VERSION 5.8 ;
BUSBITCHARS "[]" ;
DIVIDERCHAR "/" ;
UNITS
    DATABASE MICRONS 1000 ;
END UNITS

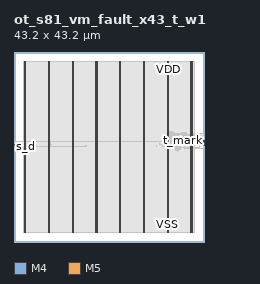
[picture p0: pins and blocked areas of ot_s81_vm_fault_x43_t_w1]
MACRO ot_s81_vm_fault_x43_t_w1
  FOREIGN ot_s81_vm_fault_x43_t_w1 0 0 ;
  CLASS BLOCK ;
  SIZE 43.2 BY 43.2 ;
  PIN b0[0]
    DIRECTION OUTPUT ;
    USE SIGNAL ;
    PORT
      LAYER M4 ;
        RECT  43.116 22.032 43.2 22.056 ;
    END
  END b0[0]
  PIN b0[1]
    DIRECTION OUTPUT ;
    USE SIGNAL ;
    PORT
      LAYER M4 ;
        RECT  43.116 22.128 43.2 22.152 ;
    END
  END b0[1]
  PIN b2[0]
    DIRECTION OUTPUT ;
    USE SIGNAL ;
    PORT
      LAYER M4 ;
        RECT  43.116 22.224 43.2 22.248 ;
    END
  END b2[0]
  PIN b2[1]
    DIRECTION OUTPUT ;
    USE SIGNAL ;
    PORT
      LAYER M4 ;
        RECT  43.116 22.32 43.2 22.344 ;
    END
  END b2[1]
  PIN b3[0]
    DIRECTION OUTPUT ;
    USE SIGNAL ;
    PORT
      LAYER M4 ;
        RECT  43.116 22.416 43.2 22.44 ;
    END
  END b3[0]
  PIN b3[1]
    DIRECTION OUTPUT ;
    USE SIGNAL ;
    PORT
      LAYER M4 ;
        RECT  43.116 22.512 43.2 22.536 ;
    END
  END b3[1]
  PIN bpar[0]
    DIRECTION OUTPUT ;
    USE SIGNAL ;
    PORT
      LAYER M4 ;
        RECT  43.116 22.608 43.2 22.632 ;
    END
  END bpar[0]
  PIN bpar[1]
    DIRECTION OUTPUT ;
    USE SIGNAL ;
    PORT
      LAYER M4 ;
        RECT  43.116 22.704 43.2 22.728 ;
    END
  END bpar[1]
  PIN bpar[2]
    DIRECTION OUTPUT ;
    USE SIGNAL ;
    PORT
      LAYER M4 ;
        RECT  43.116 22.8 43.2 22.824 ;
    END
  END bpar[2]
  PIN ph1_bad
    DIRECTION OUTPUT ;
    USE SIGNAL ;
    PORT
      LAYER M4 ;
        RECT  43.116 22.896 43.2 22.92 ;
    END
  END ph1_bad
  PIN s_d
    DIRECTION INPUT ;
    USE SIGNAL ;
    PORT
      LAYER M4 ;
        RECT  0 21.744 0.084 21.768 ;
    END
  END s_d
  PIN s_v
    DIRECTION INPUT ;
    USE SIGNAL ;
    PORT
      LAYER M4 ;
        RECT  0 21.84 0.084 21.864 ;
    END
  END s_v
  PIN t_ck
    DIRECTION INPUT ;
    USE SIGNAL ;
    PORT
      LAYER M4 ;
        RECT  0 21.936 0.084 21.96 ;
    END
  END t_ck
  PIN t_mark
    DIRECTION OUTPUT ;
    USE SIGNAL ;
    PORT
      LAYER M4 ;
        RECT  43.116 22.992 43.2 23.016 ;
    END
  END t_mark
  PIN t_rst_n
    DIRECTION INPUT ;
    USE SIGNAL ;
    PORT
      LAYER M4 ;
        RECT  0 22.032 0.084 22.056 ;
    END
  END t_rst_n
  PIN VDD
    DIRECTION INOUT ;
    USE POWER ;
    PORT
      LAYER M5 ;
        RECT  40.392 2.151 40.512 41.049 ;
        RECT  34.992 2.151 35.112 41.049 ;
        RECT  29.592 2.151 29.712 41.049 ;
        RECT  24.192 2.151 24.312 41.049 ;
        RECT  18.792 2.151 18.912 41.049 ;
        RECT  13.392 2.151 13.512 41.049 ;
        RECT  7.992 2.151 8.112 41.049 ;
        RECT  2.592 2.151 2.712 41.049 ;
    END
  END VDD
  PIN VSS
    DIRECTION INOUT ;
    USE GROUND ;
    PORT
      LAYER M5 ;
        RECT  40.2 2.137 40.32 41.063 ;
        RECT  34.8 2.137 34.92 41.063 ;
        RECT  29.4 2.137 29.52 41.063 ;
        RECT  24 2.137 24.12 41.063 ;
        RECT  18.6 2.137 18.72 41.063 ;
        RECT  13.2 2.137 13.32 41.063 ;
        RECT  7.8 2.137 7.92 41.063 ;
        RECT  2.4 2.137 2.52 41.063 ;
    END
  END VSS
  # OT_OBS_CLOSED layer=M5 d_um=1.536 added=1
  OBS
    LAYER RVTN ;
     RECT  2.16 2.16 41.04 2.295 ;
     RECT  2.16 2.565 41.04 2.835 ;
     RECT  2.16 3.105 41.04 3.375 ;
     RECT  2.16 3.645 41.04 3.915 ;
     RECT  2.16 4.185 41.04 4.455 ;
     RECT  2.16 4.725 41.04 4.995 ;
     RECT  2.16 5.265 41.04 5.535 ;
     RECT  2.16 5.805 41.04 6.075 ;
     RECT  2.16 6.345 41.04 6.615 ;
     RECT  2.16 6.885 41.04 7.155 ;
     RECT  2.16 7.425 41.04 7.695 ;
     RECT  2.16 7.965 41.04 8.235 ;
     RECT  2.16 8.505 41.04 8.775 ;
     RECT  2.16 9.045 41.04 9.315 ;
     RECT  2.16 9.585 41.04 9.855 ;
     RECT  2.16 10.125 41.04 10.395 ;
     RECT  2.16 10.665 41.04 10.935 ;
     RECT  2.16 11.205 41.04 11.475 ;
     RECT  2.16 11.745 41.04 12.015 ;
     RECT  2.16 12.285 41.04 12.555 ;
     RECT  2.16 12.825 41.04 13.095 ;
     RECT  2.16 13.365 41.04 13.635 ;
     RECT  2.16 13.905 41.04 14.175 ;
     RECT  2.16 14.445 41.04 14.715 ;
     RECT  2.16 14.985 41.04 15.255 ;
     RECT  2.16 15.525 41.04 15.795 ;
     RECT  2.16 16.065 41.04 16.335 ;
     RECT  2.16 16.605 41.04 16.875 ;
     RECT  2.16 17.145 41.04 17.415 ;
     RECT  2.16 17.685 41.04 17.955 ;
     RECT  2.16 18.225 41.04 18.495 ;
     RECT  2.16 18.765 41.04 19.035 ;
     RECT  2.16 19.305 41.04 19.575 ;
     RECT  2.16 19.845 41.04 20.115 ;
     RECT  2.16 20.385 41.04 20.655 ;
     RECT  2.16 20.925 41.04 21.195 ;
     RECT  2.16 21.465 41.04 21.735 ;
     RECT  2.16 22.005 41.04 22.275 ;
     RECT  2.16 22.545 41.04 22.815 ;
     RECT  2.16 23.085 41.04 23.355 ;
     RECT  2.16 23.625 41.04 23.895 ;
     RECT  2.16 24.165 41.04 24.435 ;
     RECT  2.16 24.705 41.04 24.975 ;
     RECT  2.16 25.245 41.04 25.515 ;
     RECT  2.16 25.785 41.04 26.055 ;
     RECT  2.16 26.325 41.04 26.595 ;
     RECT  2.16 26.865 41.04 27.135 ;
     RECT  2.16 27.405 41.04 27.675 ;
     RECT  2.16 27.945 41.04 28.215 ;
     RECT  2.16 28.485 41.04 28.755 ;
     RECT  2.16 29.025 41.04 29.295 ;
     RECT  2.16 29.565 41.04 29.835 ;
     RECT  2.16 30.105 41.04 30.375 ;
     RECT  2.16 30.645 41.04 30.915 ;
     RECT  2.16 31.185 41.04 31.455 ;
     RECT  2.16 31.725 41.04 31.995 ;
     RECT  2.16 32.265 41.04 32.535 ;
     RECT  2.16 32.805 41.04 33.075 ;
     RECT  2.16 33.345 41.04 33.615 ;
     RECT  2.16 33.885 41.04 34.155 ;
     RECT  2.16 34.425 41.04 34.695 ;
     RECT  2.16 34.965 41.04 35.235 ;
     RECT  2.16 35.505 41.04 35.775 ;
     RECT  2.16 36.045 41.04 36.315 ;
     RECT  2.16 36.585 41.04 36.855 ;
     RECT  2.16 37.125 41.04 37.395 ;
     RECT  2.16 37.665 41.04 37.935 ;
     RECT  2.16 38.205 41.04 38.475 ;
     RECT  2.16 38.745 41.04 39.015 ;
     RECT  2.16 39.285 41.04 39.555 ;
     RECT  2.16 39.825 41.04 40.095 ;
     RECT  2.16 40.365 41.04 40.635 ;
     RECT  2.16 40.905 41.04 41.04 ;
    LAYER RVTP ;
     RECT  2.16 2.295 41.04 2.565 ;
     RECT  2.16 2.835 41.04 3.105 ;
     RECT  2.16 3.375 41.04 3.645 ;
     RECT  2.16 3.915 41.04 4.185 ;
     RECT  2.16 4.455 41.04 4.725 ;
     RECT  2.16 4.995 41.04 5.265 ;
     RECT  2.16 5.535 41.04 5.805 ;
     RECT  2.16 6.075 41.04 6.345 ;
     RECT  2.16 6.615 41.04 6.885 ;
     RECT  2.16 7.155 41.04 7.425 ;
     RECT  2.16 7.695 41.04 7.965 ;
     RECT  2.16 8.235 41.04 8.505 ;
     RECT  2.16 8.775 41.04 9.045 ;
     RECT  2.16 9.315 41.04 9.585 ;
     RECT  2.16 9.855 41.04 10.125 ;
     RECT  2.16 10.395 41.04 10.665 ;
     RECT  2.16 10.935 41.04 11.205 ;
     RECT  2.16 11.475 41.04 11.745 ;
     RECT  2.16 12.015 41.04 12.285 ;
     RECT  2.16 12.555 41.04 12.825 ;
     RECT  2.16 13.095 41.04 13.365 ;
     RECT  2.16 13.635 41.04 13.905 ;
     RECT  2.16 14.175 41.04 14.445 ;
     RECT  2.16 14.715 41.04 14.985 ;
     RECT  2.16 15.255 41.04 15.525 ;
     RECT  2.16 15.795 41.04 16.065 ;
     RECT  2.16 16.335 41.04 16.605 ;
     RECT  2.16 16.875 41.04 17.145 ;
     RECT  2.16 17.415 41.04 17.685 ;
     RECT  2.16 17.955 41.04 18.225 ;
     RECT  2.16 18.495 41.04 18.765 ;
     RECT  2.16 19.035 41.04 19.305 ;
     RECT  2.16 19.575 41.04 19.845 ;
     RECT  2.16 20.115 41.04 20.385 ;
     RECT  2.16 20.655 41.04 20.925 ;
     RECT  2.16 21.195 41.04 21.465 ;
     RECT  2.16 21.735 41.04 22.005 ;
     RECT  2.16 22.275 41.04 22.545 ;
     RECT  2.16 22.815 41.04 23.085 ;
     RECT  2.16 23.355 41.04 23.625 ;
     RECT  2.16 23.895 41.04 24.165 ;
     RECT  2.16 24.435 41.04 24.705 ;
     RECT  2.16 24.975 41.04 25.245 ;
     RECT  2.16 25.515 41.04 25.785 ;
     RECT  2.16 26.055 41.04 26.325 ;
     RECT  2.16 26.595 41.04 26.865 ;
     RECT  2.16 27.135 41.04 27.405 ;
     RECT  2.16 27.675 41.04 27.945 ;
     RECT  2.16 28.215 41.04 28.485 ;
     RECT  2.16 28.755 41.04 29.025 ;
     RECT  2.16 29.295 41.04 29.565 ;
     RECT  2.16 29.835 41.04 30.105 ;
     RECT  2.16 30.375 41.04 30.645 ;
     RECT  2.16 30.915 41.04 31.185 ;
     RECT  2.16 31.455 41.04 31.725 ;
     RECT  2.16 31.995 41.04 32.265 ;
     RECT  2.16 32.535 41.04 32.805 ;
     RECT  2.16 33.075 41.04 33.345 ;
     RECT  2.16 33.615 41.04 33.885 ;
     RECT  2.16 34.155 41.04 34.425 ;
     RECT  2.16 34.695 41.04 34.965 ;
     RECT  2.16 35.235 41.04 35.505 ;
     RECT  2.16 35.775 41.04 36.045 ;
     RECT  2.16 36.315 41.04 36.585 ;
     RECT  2.16 36.855 41.04 37.125 ;
     RECT  2.16 37.395 41.04 37.665 ;
     RECT  2.16 37.935 41.04 38.205 ;
     RECT  2.16 38.475 41.04 38.745 ;
     RECT  2.16 39.015 41.04 39.285 ;
     RECT  2.16 39.555 41.04 39.825 ;
     RECT  2.16 40.095 41.04 40.365 ;
     RECT  2.16 40.635 41.04 40.905 ;
    LAYER M1 ;
     RECT  2.16 2.151 41.04 41.049 ;
    LAYER M2 ;
     RECT  2.16 2.151 41.04 41.049 ;
     RECT  41.04 22.626 42.143 23.04 ;
     RECT  42.143 22.986 42.179 23.004 ;
     RECT  41.04 21.276 42.215 21.564 ;
     RECT  42.215 21.276 43.115 21.294 ;
     RECT  41.04 24.066 43.115 24.624 ;
     RECT  43.087 22.518 43.187 22.536 ;
     RECT  43.115 24.606 43.187 24.624 ;
    LAYER M3 ;
     RECT  2.415 2.143 2.505 2.413 ;
     RECT  7.815 2.143 7.905 2.413 ;
     RECT  13.215 2.143 13.305 2.413 ;
     RECT  18.615 2.143 18.705 2.413 ;
     RECT  24.015 2.143 24.105 2.413 ;
     RECT  29.415 2.143 29.505 2.413 ;
     RECT  34.815 2.143 34.905 2.413 ;
     RECT  40.215 2.143 40.305 2.413 ;
     RECT  37.08 20.551 37.098 20.695 ;
     RECT  36.864 20.695 37.386 20.893 ;
     RECT  36.684 20.893 37.386 20.929 ;
     RECT  36.648 20.929 37.386 20.965 ;
     RECT  36.648 20.965 37.602 21.001 ;
     RECT  36.648 21.001 37.746 21.127 ;
     RECT  34.815 2.413 35.097 21.163 ;
     RECT  40.215 2.413 40.497 21.235 ;
     RECT  36.648 21.127 37.782 21.271 ;
     RECT  39.528 21.235 40.554 21.271 ;
     RECT  36.648 21.271 37.89 21.433 ;
     RECT  38.808 21.271 40.554 21.433 ;
     RECT  36.648 21.433 40.554 21.469 ;
     RECT  34.815 21.163 35.406 21.505 ;
     RECT  36.648 21.469 40.914 21.505 ;
     RECT  36.648 21.505 41.022 21.533 ;
     RECT  34.776 21.505 35.622 21.541 ;
     RECT  36.648 21.533 37.962 21.541 ;
     RECT  34.776 21.541 37.962 21.695 ;
     RECT  33.84 21.691 33.858 21.775 ;
     RECT  34.776 21.695 35.55 21.775 ;
     RECT  16.236 21.739 16.254 21.811 ;
     RECT  32.436 21.667 32.454 21.839 ;
     RECT  36.468 21.695 37.962 21.929 ;
     RECT  16.236 21.811 16.434 21.965 ;
     RECT  33.84 21.775 35.55 22.001 ;
     RECT  7.815 2.413 8.097 22.027 ;
     RECT  7.815 22.027 8.37 22.081 ;
     RECT  33.84 22.001 33.858 22.081 ;
     RECT  42.192 21.541 42.21 22.157 ;
     RECT  33.264 22.081 33.858 22.171 ;
     RECT  7.815 22.081 8.55 22.199 ;
     RECT  33.084 22.171 33.858 22.199 ;
     RECT  7.815 22.199 8.37 22.235 ;
     RECT  16.56 22.081 16.578 22.235 ;
     RECT  33.84 22.199 33.858 22.235 ;
     RECT  38.736 21.533 41.022 22.253 ;
     RECT  33.084 22.199 33.102 22.343 ;
     RECT  38.736 22.253 40.914 22.351 ;
     RECT  34.668 22.001 35.55 22.441 ;
     RECT  36.468 21.929 37.71 22.441 ;
     RECT  34.668 22.441 37.71 22.505 ;
     RECT  43.092 21.271 43.11 22.513 ;
     RECT  42.156 22.411 42.174 22.621 ;
     RECT  38.52 22.351 40.914 22.739 ;
     RECT  34.776 22.505 37.71 22.783 ;
     RECT  38.52 22.739 40.734 22.783 ;
     RECT  43.092 22.513 43.182 22.795 ;
     RECT  34.776 22.783 40.734 22.811 ;
     RECT  42.12 22.621 42.174 22.891 ;
     RECT  42.12 22.891 42.21 23.045 ;
     RECT  34.776 22.811 37.242 23.557 ;
     RECT  38.052 22.811 40.734 23.557 ;
     RECT  42.192 23.045 42.21 24.161 ;
     RECT  34.776 23.557 40.734 24.205 ;
     RECT  34.056 24.205 40.734 24.359 ;
     RECT  43.056 22.795 43.182 24.359 ;
     RECT  34.056 24.359 39.33 24.395 ;
     RECT  34.056 24.395 39.15 24.503 ;
     RECT  34.776 24.503 39.15 24.629 ;
     RECT  43.164 24.359 43.182 24.629 ;
     RECT  34.815 24.629 36.594 24.665 ;
     RECT  40.215 24.359 40.734 24.665 ;
     RECT  37.692 24.629 39.15 24.773 ;
     RECT  38.124 24.773 39.15 24.809 ;
     RECT  38.412 24.809 39.15 24.899 ;
     RECT  34.815 24.665 36.486 24.935 ;
     RECT  38.412 24.899 39.042 24.935 ;
     RECT  34.815 24.935 35.946 25.079 ;
     RECT  35.928 25.079 35.946 25.169 ;
     RECT  2.415 2.413 2.697 40.787 ;
     RECT  7.815 22.235 8.097 40.787 ;
     RECT  13.215 2.413 13.497 40.787 ;
     RECT  18.615 2.413 18.897 40.787 ;
     RECT  24.015 2.413 24.297 40.787 ;
     RECT  29.415 2.413 29.697 40.787 ;
     RECT  34.815 25.079 35.097 40.787 ;
     RECT  40.215 24.665 40.497 40.787 ;
     RECT  2.415 40.787 2.505 41.057 ;
     RECT  7.815 40.787 7.905 41.057 ;
     RECT  13.215 40.787 13.305 41.057 ;
     RECT  18.615 40.787 18.705 41.057 ;
     RECT  24.015 40.787 24.105 41.057 ;
     RECT  29.415 40.787 29.505 41.057 ;
     RECT  34.815 40.787 34.905 41.057 ;
     RECT  40.215 40.787 40.305 41.057 ;
    LAYER M4 ;
     RECT  0.084 21.744 0.133 21.768 ;
     RECT  0.06 21.768 0.133 21.84 ;
     RECT  0.084 21.84 0.133 21.864 ;
     RECT  0.06 21.864 0.133 21.936 ;
     RECT  0.084 21.936 0.133 21.96 ;
     RECT  0.06 21.96 0.133 22.032 ;
     RECT  0.084 22.032 0.133 22.056 ;
     RECT  0.133 21.744 2.408 22.824 ;
     RECT  2.408 2.148 2.512 41.052 ;
     RECT  2.512 2.418 2.704 40.782 ;
     RECT  2.704 21.744 7.808 22.824 ;
     RECT  7.808 2.148 7.912 41.052 ;
     RECT  7.912 2.418 8.104 40.782 ;
     RECT  8.104 21.744 8.381 22.824 ;
     RECT  8.381 21.744 13.208 21.768 ;
     RECT  8.381 22.8 13.208 22.824 ;
     RECT  13.208 2.148 13.312 41.052 ;
     RECT  13.312 2.418 13.504 40.782 ;
     RECT  13.504 21.744 16.265 21.768 ;
     RECT  13.504 22.8 18.608 22.824 ;
     RECT  18.608 2.148 18.712 41.052 ;
     RECT  18.712 2.418 18.904 40.782 ;
     RECT  18.904 22.8 24.008 22.824 ;
     RECT  24.008 2.148 24.112 41.052 ;
     RECT  24.112 2.418 24.304 40.782 ;
     RECT  24.304 22.8 29.408 22.824 ;
     RECT  29.408 2.148 29.512 41.052 ;
     RECT  29.512 2.418 29.704 40.782 ;
     RECT  33.829 21.696 34.765 21.72 ;
     RECT  34.765 21.696 34.808 21.816 ;
     RECT  29.704 22.8 34.808 22.824 ;
     RECT  34.808 2.148 34.912 41.052 ;
     RECT  34.912 2.418 35.104 40.782 ;
     RECT  35.104 21.648 35.417 24.648 ;
     RECT  35.417 21.648 35.603 21.672 ;
     RECT  35.417 22.752 35.644 24.648 ;
     RECT  35.644 22.8 35.921 24.648 ;
     RECT  35.921 22.8 35.957 24.12 ;
     RECT  35.957 22.896 36.137 24.12 ;
     RECT  36.137 23.088 36.803 24.12 ;
     RECT  36.803 23.232 36.893 24.12 ;
     RECT  36.893 23.328 37.253 24.12 ;
     RECT  37.253 23.904 37.393 24.12 ;
     RECT  37.537 21.696 37.649 21.72 ;
     RECT  37.393 23.904 38.401 24.504 ;
     RECT  38.401 23.568 38.513 24.504 ;
     RECT  38.513 23.568 38.801 23.592 ;
     RECT  40.208 2.148 40.312 41.052 ;
     RECT  40.312 2.418 40.504 40.782 ;
     RECT  40.504 22.224 42.109 22.344 ;
     RECT  42.109 22.224 42.181 23.016 ;
     RECT  42.181 22.128 43.081 23.016 ;
     RECT  43.081 22.032 43.116 22.056 ;
     RECT  43.081 22.056 43.164 22.128 ;
     RECT  43.081 22.128 43.116 22.152 ;
     RECT  43.081 22.152 43.164 22.224 ;
     RECT  43.081 22.224 43.116 22.248 ;
     RECT  43.081 22.248 43.164 22.32 ;
     RECT  43.081 22.32 43.116 22.344 ;
     RECT  43.081 22.344 43.164 22.416 ;
     RECT  43.081 22.416 43.116 22.44 ;
     RECT  43.081 22.44 43.164 22.512 ;
     RECT  43.081 22.512 43.116 22.536 ;
     RECT  43.081 22.536 43.164 22.608 ;
     RECT  43.081 22.608 43.116 22.632 ;
     RECT  43.081 22.632 43.164 22.704 ;
     RECT  43.081 22.704 43.116 22.728 ;
     RECT  43.081 22.728 43.164 22.8 ;
     RECT  43.081 22.8 43.116 22.824 ;
     RECT  43.081 22.824 43.164 22.896 ;
     RECT  43.081 22.896 43.116 22.92 ;
     RECT  43.081 22.92 43.164 22.992 ;
     RECT  43.081 22.992 43.116 23.016 ;
    LAYER M5 ;
     RECT  2.4 2.137 2.52 2.151 ;
     RECT  7.8 2.137 7.92 2.151 ;
     RECT  13.2 2.137 13.32 2.151 ;
     RECT  18.6 2.137 18.72 2.151 ;
     RECT  24 2.137 24.12 2.151 ;
     RECT  29.4 2.137 29.52 2.151 ;
     RECT  34.8 2.137 34.92 2.151 ;
     RECT  40.2 2.137 40.32 2.151 ;
     RECT  34.8 2.151 35.112 21.637 ;
     RECT  0.144 21.925 0.168 22.835 ;
     RECT  34.8 21.637 35.592 23.267 ;
     RECT  36.768 23.077 36.792 23.411 ;
     RECT  2.4 2.151 2.712 41.049 ;
     RECT  7.8 2.151 8.112 41.049 ;
     RECT  13.2 2.151 13.512 41.049 ;
     RECT  18.6 2.151 18.912 41.049 ;
     RECT  24 2.151 24.312 41.049 ;
     RECT  29.4 2.151 29.712 41.049 ;
     RECT  34.8 23.267 35.112 41.049 ;
     RECT  40.2 2.151 40.512 41.049 ;
     RECT  2.4 41.049 2.52 41.063 ;
     RECT  7.8 41.049 7.92 41.063 ;
     RECT  13.2 41.049 13.32 41.063 ;
     RECT  18.6 41.049 18.72 41.063 ;
     RECT  24 41.049 24.12 41.063 ;
     RECT  29.4 41.049 29.52 41.063 ;
     RECT  34.8 41.049 34.92 41.063 ;
     RECT  40.2 41.049 40.32 41.063 ;
     RECT  35.592 23.077 36.768 23.267 ;
  END
END ot_s81_vm_fault_x43_t_w1
END LIBRARY
